VERSION 5.7 ;
BUSBITCHARS "[]" ;
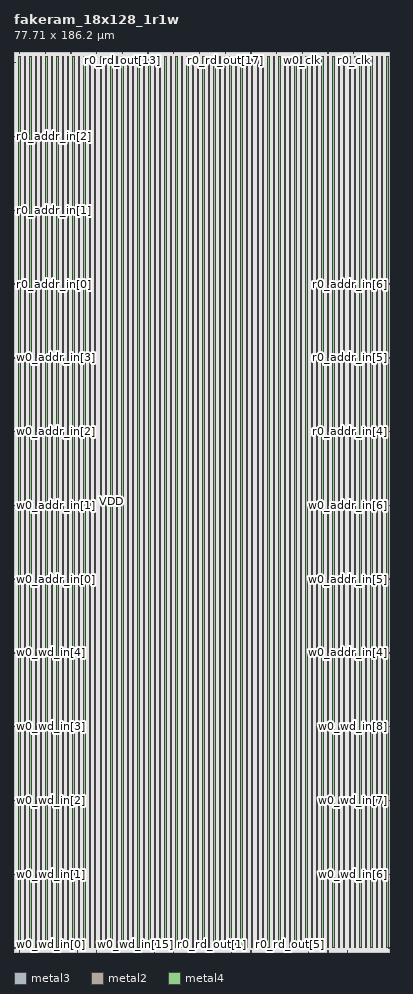
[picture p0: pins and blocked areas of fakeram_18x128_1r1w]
MACRO fakeram_18x128_1r1w
  FOREIGN fakeram_18x128_1r1w 0 0 ;
  SYMMETRY X Y R90 ;
  SIZE 77.710 BY 186.200 ;
  CLASS BLOCK ;
  PIN w0_wd_in[0]
    DIRECTION INPUT ;
    USE SIGNAL ;
    SHAPE ABUTMENT ;
    PORT
      LAYER metal3 ;
      RECT 0.000 0.805 0.210 0.875 ;
    END
  END w0_wd_in[0]
  PIN w0_wd_in[1]
    DIRECTION INPUT ;
    USE SIGNAL ;
    SHAPE ABUTMENT ;
    PORT
      LAYER metal3 ;
      RECT 0.000 16.065 0.210 16.135 ;
    END
  END w0_wd_in[1]
  PIN w0_wd_in[2]
    DIRECTION INPUT ;
    USE SIGNAL ;
    SHAPE ABUTMENT ;
    PORT
      LAYER metal3 ;
      RECT 0.000 31.325 0.210 31.395 ;
    END
  END w0_wd_in[2]
  PIN w0_wd_in[3]
    DIRECTION INPUT ;
    USE SIGNAL ;
    SHAPE ABUTMENT ;
    PORT
      LAYER metal3 ;
      RECT 0.000 46.585 0.210 46.655 ;
    END
  END w0_wd_in[3]
  PIN w0_wd_in[4]
    DIRECTION INPUT ;
    USE SIGNAL ;
    SHAPE ABUTMENT ;
    PORT
      LAYER metal3 ;
      RECT 0.000 61.845 0.210 61.915 ;
    END
  END w0_wd_in[4]
  PIN w0_wd_in[5]
    DIRECTION INPUT ;
    USE SIGNAL ;
    SHAPE ABUTMENT ;
    PORT
      LAYER metal3 ;
      RECT 77.500 0.805 77.710 0.875 ;
    END
  END w0_wd_in[5]
  PIN w0_wd_in[6]
    DIRECTION INPUT ;
    USE SIGNAL ;
    SHAPE ABUTMENT ;
    PORT
      LAYER metal3 ;
      RECT 77.500 16.065 77.710 16.135 ;
    END
  END w0_wd_in[6]
  PIN w0_wd_in[7]
    DIRECTION INPUT ;
    USE SIGNAL ;
    SHAPE ABUTMENT ;
    PORT
      LAYER metal3 ;
      RECT 77.500 31.325 77.710 31.395 ;
    END
  END w0_wd_in[7]
  PIN w0_wd_in[8]
    DIRECTION INPUT ;
    USE SIGNAL ;
    SHAPE ABUTMENT ;
    PORT
      LAYER metal3 ;
      RECT 77.500 46.585 77.710 46.655 ;
    END
  END w0_wd_in[8]
  PIN w0_wd_in[9]
    DIRECTION INPUT ;
    USE SIGNAL ;
    SHAPE ABUTMENT ;
    PORT
      LAYER metal2 ;
      RECT 1.105 0.000 1.175 0.210 ;
    END
  END w0_wd_in[9]
  PIN w0_wd_in[10]
    DIRECTION INPUT ;
    USE SIGNAL ;
    SHAPE ABUTMENT ;
    PORT
      LAYER metal2 ;
      RECT 5.095 0.000 5.165 0.210 ;
    END
  END w0_wd_in[10]
  PIN w0_wd_in[11]
    DIRECTION INPUT ;
    USE SIGNAL ;
    SHAPE ABUTMENT ;
    PORT
      LAYER metal2 ;
      RECT 9.085 0.000 9.155 0.210 ;
    END
  END w0_wd_in[11]
  PIN w0_wd_in[12]
    DIRECTION INPUT ;
    USE SIGNAL ;
    SHAPE ABUTMENT ;
    PORT
      LAYER metal2 ;
      RECT 13.075 0.000 13.145 0.210 ;
    END
  END w0_wd_in[12]
  PIN w0_wd_in[13]
    DIRECTION INPUT ;
    USE SIGNAL ;
    SHAPE ABUTMENT ;
    PORT
      LAYER metal2 ;
      RECT 17.065 0.000 17.135 0.210 ;
    END
  END w0_wd_in[13]
  PIN w0_wd_in[14]
    DIRECTION INPUT ;
    USE SIGNAL ;
    SHAPE ABUTMENT ;
    PORT
      LAYER metal2 ;
      RECT 21.055 0.000 21.125 0.210 ;
    END
  END w0_wd_in[14]
  PIN w0_wd_in[15]
    DIRECTION INPUT ;
    USE SIGNAL ;
    SHAPE ABUTMENT ;
    PORT
      LAYER metal2 ;
      RECT 25.045 0.000 25.115 0.210 ;
    END
  END w0_wd_in[15]
  PIN w0_wd_in[16]
    DIRECTION INPUT ;
    USE SIGNAL ;
    SHAPE ABUTMENT ;
    PORT
      LAYER metal2 ;
      RECT 29.035 0.000 29.105 0.210 ;
    END
  END w0_wd_in[16]
  PIN w0_wd_in[17]
    DIRECTION INPUT ;
    USE SIGNAL ;
    SHAPE ABUTMENT ;
    PORT
      LAYER metal2 ;
      RECT 33.025 0.000 33.095 0.210 ;
    END
  END w0_wd_in[17]
  PIN r0_rd_out[0]
    DIRECTION OUTPUT ;
    USE SIGNAL ;
    SHAPE ABUTMENT ;
    PORT
      LAYER metal2 ;
      RECT 37.015 0.000 37.085 0.210 ;
    END
  END r0_rd_out[0]
  PIN r0_rd_out[1]
    DIRECTION OUTPUT ;
    USE SIGNAL ;
    SHAPE ABUTMENT ;
    PORT
      LAYER metal2 ;
      RECT 41.005 0.000 41.075 0.210 ;
    END
  END r0_rd_out[1]
  PIN r0_rd_out[2]
    DIRECTION OUTPUT ;
    USE SIGNAL ;
    SHAPE ABUTMENT ;
    PORT
      LAYER metal2 ;
      RECT 44.995 0.000 45.065 0.210 ;
    END
  END r0_rd_out[2]
  PIN r0_rd_out[3]
    DIRECTION OUTPUT ;
    USE SIGNAL ;
    SHAPE ABUTMENT ;
    PORT
      LAYER metal2 ;
      RECT 48.985 0.000 49.055 0.210 ;
    END
  END r0_rd_out[3]
  PIN r0_rd_out[4]
    DIRECTION OUTPUT ;
    USE SIGNAL ;
    SHAPE ABUTMENT ;
    PORT
      LAYER metal2 ;
      RECT 52.975 0.000 53.045 0.210 ;
    END
  END r0_rd_out[4]
  PIN r0_rd_out[5]
    DIRECTION OUTPUT ;
    USE SIGNAL ;
    SHAPE ABUTMENT ;
    PORT
      LAYER metal2 ;
      RECT 56.965 0.000 57.035 0.210 ;
    END
  END r0_rd_out[5]
  PIN r0_rd_out[6]
    DIRECTION OUTPUT ;
    USE SIGNAL ;
    SHAPE ABUTMENT ;
    PORT
      LAYER metal2 ;
      RECT 60.955 0.000 61.025 0.210 ;
    END
  END r0_rd_out[6]
  PIN r0_rd_out[7]
    DIRECTION OUTPUT ;
    USE SIGNAL ;
    SHAPE ABUTMENT ;
    PORT
      LAYER metal2 ;
      RECT 64.945 0.000 65.015 0.210 ;
    END
  END r0_rd_out[7]
  PIN r0_rd_out[8]
    DIRECTION OUTPUT ;
    USE SIGNAL ;
    SHAPE ABUTMENT ;
    PORT
      LAYER metal2 ;
      RECT 68.935 0.000 69.005 0.210 ;
    END
  END r0_rd_out[8]
  PIN r0_rd_out[9]
    DIRECTION OUTPUT ;
    USE SIGNAL ;
    SHAPE ABUTMENT ;
    PORT
      LAYER metal2 ;
      RECT 1.105 185.990 1.175 186.200 ;
    END
  END r0_rd_out[9]
  PIN r0_rd_out[10]
    DIRECTION OUTPUT ;
    USE SIGNAL ;
    SHAPE ABUTMENT ;
    PORT
      LAYER metal2 ;
      RECT 6.425 185.990 6.495 186.200 ;
    END
  END r0_rd_out[10]
  PIN r0_rd_out[11]
    DIRECTION OUTPUT ;
    USE SIGNAL ;
    SHAPE ABUTMENT ;
    PORT
      LAYER metal2 ;
      RECT 11.745 185.990 11.815 186.200 ;
    END
  END r0_rd_out[11]
  PIN r0_rd_out[12]
    DIRECTION OUTPUT ;
    USE SIGNAL ;
    SHAPE ABUTMENT ;
    PORT
      LAYER metal2 ;
      RECT 17.065 185.990 17.135 186.200 ;
    END
  END r0_rd_out[12]
  PIN r0_rd_out[13]
    DIRECTION OUTPUT ;
    USE SIGNAL ;
    SHAPE ABUTMENT ;
    PORT
      LAYER metal2 ;
      RECT 22.385 185.990 22.455 186.200 ;
    END
  END r0_rd_out[13]
  PIN r0_rd_out[14]
    DIRECTION OUTPUT ;
    USE SIGNAL ;
    SHAPE ABUTMENT ;
    PORT
      LAYER metal2 ;
      RECT 27.705 185.990 27.775 186.200 ;
    END
  END r0_rd_out[14]
  PIN r0_rd_out[15]
    DIRECTION OUTPUT ;
    USE SIGNAL ;
    SHAPE ABUTMENT ;
    PORT
      LAYER metal2 ;
      RECT 33.025 185.990 33.095 186.200 ;
    END
  END r0_rd_out[15]
  PIN r0_rd_out[16]
    DIRECTION OUTPUT ;
    USE SIGNAL ;
    SHAPE ABUTMENT ;
    PORT
      LAYER metal2 ;
      RECT 38.345 185.990 38.415 186.200 ;
    END
  END r0_rd_out[16]
  PIN r0_rd_out[17]
    DIRECTION OUTPUT ;
    USE SIGNAL ;
    SHAPE ABUTMENT ;
    PORT
      LAYER metal2 ;
      RECT 43.665 185.990 43.735 186.200 ;
    END
  END r0_rd_out[17]
  PIN w0_addr_in[0]
    DIRECTION INPUT ;
    USE SIGNAL ;
    SHAPE ABUTMENT ;
    PORT
      LAYER metal3 ;
      RECT 0.000 77.105 0.210 77.175 ;
    END
  END w0_addr_in[0]
  PIN w0_addr_in[1]
    DIRECTION INPUT ;
    USE SIGNAL ;
    SHAPE ABUTMENT ;
    PORT
      LAYER metal3 ;
      RECT 0.000 92.365 0.210 92.435 ;
    END
  END w0_addr_in[1]
  PIN w0_addr_in[2]
    DIRECTION INPUT ;
    USE SIGNAL ;
    SHAPE ABUTMENT ;
    PORT
      LAYER metal3 ;
      RECT 0.000 107.625 0.210 107.695 ;
    END
  END w0_addr_in[2]
  PIN w0_addr_in[3]
    DIRECTION INPUT ;
    USE SIGNAL ;
    SHAPE ABUTMENT ;
    PORT
      LAYER metal3 ;
      RECT 0.000 122.885 0.210 122.955 ;
    END
  END w0_addr_in[3]
  PIN w0_addr_in[4]
    DIRECTION INPUT ;
    USE SIGNAL ;
    SHAPE ABUTMENT ;
    PORT
      LAYER metal3 ;
      RECT 77.500 61.845 77.710 61.915 ;
    END
  END w0_addr_in[4]
  PIN w0_addr_in[5]
    DIRECTION INPUT ;
    USE SIGNAL ;
    SHAPE ABUTMENT ;
    PORT
      LAYER metal3 ;
      RECT 77.500 77.105 77.710 77.175 ;
    END
  END w0_addr_in[5]
  PIN w0_addr_in[6]
    DIRECTION INPUT ;
    USE SIGNAL ;
    SHAPE ABUTMENT ;
    PORT
      LAYER metal3 ;
      RECT 77.500 92.365 77.710 92.435 ;
    END
  END w0_addr_in[6]
  PIN r0_addr_in[0]
    DIRECTION INPUT ;
    USE SIGNAL ;
    SHAPE ABUTMENT ;
    PORT
      LAYER metal3 ;
      RECT 0.000 138.145 0.210 138.215 ;
    END
  END r0_addr_in[0]
  PIN r0_addr_in[1]
    DIRECTION INPUT ;
    USE SIGNAL ;
    SHAPE ABUTMENT ;
    PORT
      LAYER metal3 ;
      RECT 0.000 153.405 0.210 153.475 ;
    END
  END r0_addr_in[1]
  PIN r0_addr_in[2]
    DIRECTION INPUT ;
    USE SIGNAL ;
    SHAPE ABUTMENT ;
    PORT
      LAYER metal3 ;
      RECT 0.000 168.665 0.210 168.735 ;
    END
  END r0_addr_in[2]
  PIN r0_addr_in[3]
    DIRECTION INPUT ;
    USE SIGNAL ;
    SHAPE ABUTMENT ;
    PORT
      LAYER metal3 ;
      RECT 0.000 183.925 0.210 183.995 ;
    END
  END r0_addr_in[3]
  PIN r0_addr_in[4]
    DIRECTION INPUT ;
    USE SIGNAL ;
    SHAPE ABUTMENT ;
    PORT
      LAYER metal3 ;
      RECT 77.500 107.625 77.710 107.695 ;
    END
  END r0_addr_in[4]
  PIN r0_addr_in[5]
    DIRECTION INPUT ;
    USE SIGNAL ;
    SHAPE ABUTMENT ;
    PORT
      LAYER metal3 ;
      RECT 77.500 122.885 77.710 122.955 ;
    END
  END r0_addr_in[5]
  PIN r0_addr_in[6]
    DIRECTION INPUT ;
    USE SIGNAL ;
    SHAPE ABUTMENT ;
    PORT
      LAYER metal3 ;
      RECT 77.500 138.145 77.710 138.215 ;
    END
  END r0_addr_in[6]
  PIN w0_we_in
    DIRECTION INPUT ;
    USE SIGNAL ;
    SHAPE ABUTMENT ;
    PORT
      LAYER metal2 ;
      RECT 48.985 185.990 49.055 186.200 ;
    END
  END w0_we_in
  PIN w0_ce_in
    DIRECTION INPUT ;
    USE SIGNAL ;
    SHAPE ABUTMENT ;
    PORT
      LAYER metal2 ;
      RECT 54.305 185.990 54.375 186.200 ;
    END
  END w0_ce_in
  PIN w0_clk
    DIRECTION INPUT ;
    USE SIGNAL ;
    SHAPE ABUTMENT ;
    PORT
      LAYER metal2 ;
      RECT 59.625 185.990 59.695 186.200 ;
    END
  END w0_clk
  PIN r0_ce_in
    DIRECTION INPUT ;
    USE SIGNAL ;
    SHAPE ABUTMENT ;
    PORT
      LAYER metal2 ;
      RECT 64.945 185.990 65.015 186.200 ;
    END
  END r0_ce_in
  PIN r0_clk
    DIRECTION INPUT ;
    USE SIGNAL ;
    SHAPE ABUTMENT ;
    PORT
      LAYER metal2 ;
      RECT 70.265 185.990 70.335 186.200 ;
    END
  END r0_clk
  PIN VSS
    DIRECTION INOUT ;
    USE GROUND ;
    PORT
      LAYER metal4 ;
      RECT 1.000 0.840 1.280 185.360 ;
      RECT 3.240 0.840 3.520 185.360 ;
      RECT 5.480 0.840 5.760 185.360 ;
      RECT 7.720 0.840 8.000 185.360 ;
      RECT 9.960 0.840 10.240 185.360 ;
      RECT 12.200 0.840 12.480 185.360 ;
      RECT 14.440 0.840 14.720 185.360 ;
      RECT 16.680 0.840 16.960 185.360 ;
      RECT 18.920 0.840 19.200 185.360 ;
      RECT 21.160 0.840 21.440 185.360 ;
      RECT 23.400 0.840 23.680 185.360 ;
      RECT 25.640 0.840 25.920 185.360 ;
      RECT 27.880 0.840 28.160 185.360 ;
      RECT 30.120 0.840 30.400 185.360 ;
      RECT 32.360 0.840 32.640 185.360 ;
      RECT 34.600 0.840 34.880 185.360 ;
      RECT 36.840 0.840 37.120 185.360 ;
      RECT 39.080 0.840 39.360 185.360 ;
      RECT 41.320 0.840 41.600 185.360 ;
      RECT 43.560 0.840 43.840 185.360 ;
      RECT 45.800 0.840 46.080 185.360 ;
      RECT 48.040 0.840 48.320 185.360 ;
      RECT 50.280 0.840 50.560 185.360 ;
      RECT 52.520 0.840 52.800 185.360 ;
      RECT 54.760 0.840 55.040 185.360 ;
      RECT 57.000 0.840 57.280 185.360 ;
      RECT 59.240 0.840 59.520 185.360 ;
      RECT 61.480 0.840 61.760 185.360 ;
      RECT 63.720 0.840 64.000 185.360 ;
      RECT 65.960 0.840 66.240 185.360 ;
      RECT 68.200 0.840 68.480 185.360 ;
      RECT 70.440 0.840 70.720 185.360 ;
      RECT 72.680 0.840 72.960 185.360 ;
      RECT 74.920 0.840 75.200 185.360 ;
      RECT 77.160 0.840 77.440 185.360 ;
    END
  END VSS
  PIN VDD
    DIRECTION INOUT ;
    USE POWER ;
    PORT
      LAYER metal4 ;
      RECT 2.120 0.840 2.400 185.360 ;
      RECT 4.360 0.840 4.640 185.360 ;
      RECT 6.600 0.840 6.880 185.360 ;
      RECT 8.840 0.840 9.120 185.360 ;
      RECT 11.080 0.840 11.360 185.360 ;
      RECT 13.320 0.840 13.600 185.360 ;
      RECT 15.560 0.840 15.840 185.360 ;
      RECT 17.800 0.840 18.080 185.360 ;
      RECT 20.040 0.840 20.320 185.360 ;
      RECT 22.280 0.840 22.560 185.360 ;
      RECT 24.520 0.840 24.800 185.360 ;
      RECT 26.760 0.840 27.040 185.360 ;
      RECT 29.000 0.840 29.280 185.360 ;
      RECT 31.240 0.840 31.520 185.360 ;
      RECT 33.480 0.840 33.760 185.360 ;
      RECT 35.720 0.840 36.000 185.360 ;
      RECT 37.960 0.840 38.240 185.360 ;
      RECT 40.200 0.840 40.480 185.360 ;
      RECT 42.440 0.840 42.720 185.360 ;
      RECT 44.680 0.840 44.960 185.360 ;
      RECT 46.920 0.840 47.200 185.360 ;
      RECT 49.160 0.840 49.440 185.360 ;
      RECT 51.400 0.840 51.680 185.360 ;
      RECT 53.640 0.840 53.920 185.360 ;
      RECT 55.880 0.840 56.160 185.360 ;
      RECT 58.120 0.840 58.400 185.360 ;
      RECT 60.360 0.840 60.640 185.360 ;
      RECT 62.600 0.840 62.880 185.360 ;
      RECT 64.840 0.840 65.120 185.360 ;
      RECT 67.080 0.840 67.360 185.360 ;
      RECT 69.320 0.840 69.600 185.360 ;
      RECT 71.560 0.840 71.840 185.360 ;
      RECT 73.800 0.840 74.080 185.360 ;
      RECT 76.040 0.840 76.320 185.360 ;
    END
  END VDD
  OBS
    LAYER metal1 ;
    RECT 0 0 77.710 186.200 ;
    LAYER metal2 ;
    RECT 0 0 77.710 186.200 ;
    LAYER metal3 ;
    RECT 0 0 77.710 186.200 ;
    LAYER metal4 ;
    RECT 0 0 77.710 186.200 ;
    LAYER OVERLAP ;
    RECT 0 0 77.710 186.200 ;
  END
END fakeram_18x128_1r1w

END LIBRARY
